VERSION 5.7 ;
  NOWIREEXTENSIONATPIN ON ;
  DIVIDERCHAR "/" ;
  BUSBITCHARS "[]" ;
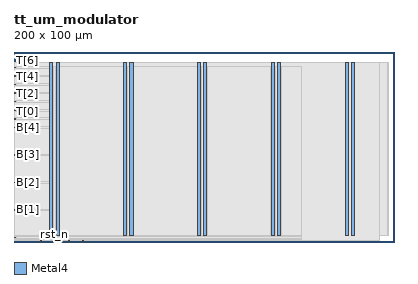
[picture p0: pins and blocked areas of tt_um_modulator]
MACRO tt_um_modulator
  CLASS BLOCK ;
  FOREIGN tt_um_modulator ;
  ORIGIN 0.000 0.000 ;
  SIZE 200.000 BY 100.000 ;
  PIN B[0]
    DIRECTION OUTPUT ;
    USE SIGNAL ;
    ANTENNADIFFAREA 1.055600 ;
    PORT
      LAYER Metal4 ;
        RECT 0.000 2.200 1.000 2.500 ;
    END
  END B[0]
  PIN B[1]
    DIRECTION OUTPUT ;
    USE SIGNAL ;
    ANTENNADIFFAREA 1.055600 ;
    PORT
      LAYER Metal4 ;
        RECT 0.000 16.700 1.000 17.000 ;
    END
  END B[1]
  PIN B[2]
    DIRECTION OUTPUT ;
    USE SIGNAL ;
    ANTENNADIFFAREA 1.055600 ;
    PORT
      LAYER Metal4 ;
        RECT 0.000 31.200 1.000 31.500 ;
    END
  END B[2]
  PIN B[3]
    DIRECTION OUTPUT ;
    USE SIGNAL ;
    ANTENNADIFFAREA 1.055600 ;
    PORT
      LAYER Metal4 ;
        RECT 0.000 45.700 1.000 46.000 ;
    END
  END B[3]
  PIN B[4]
    DIRECTION OUTPUT ;
    USE SIGNAL ;
    ANTENNADIFFAREA 1.055600 ;
    PORT
      LAYER Metal4 ;
        RECT 0.000 60.200 1.000 60.500 ;
    END
  END B[4]
  PIN T[0]
    DIRECTION OUTPUT ;
    USE SIGNAL ;
    ANTENNADIFFAREA 1.055600 ;
    PORT
      LAYER Metal4 ;
        RECT 0.000 64.700 1.000 65.000 ;
    END
  END T[0]
  PIN T[1]
    DIRECTION OUTPUT ;
    USE SIGNAL ;
    ANTENNADIFFAREA 1.055600 ;
    PORT
      LAYER Metal4 ;
        RECT 0.000 69.200 1.000 69.500 ;
    END
  END T[1]
  PIN T[2]
    DIRECTION OUTPUT ;
    USE SIGNAL ;
    ANTENNADIFFAREA 1.055600 ;
    PORT
      LAYER Metal4 ;
        RECT 0.000 73.700 1.000 74.000 ;
    END
  END T[2]
  PIN T[3]
    DIRECTION OUTPUT ;
    USE SIGNAL ;
    ANTENNADIFFAREA 1.055600 ;
    PORT
      LAYER Metal4 ;
        RECT 0.000 78.200 1.000 78.500 ;
    END
  END T[3]
  PIN T[4]
    DIRECTION OUTPUT ;
    USE SIGNAL ;
    ANTENNADIFFAREA 1.055600 ;
    PORT
      LAYER Metal4 ;
        RECT 0.000 82.700 1.000 83.000 ;
    END
  END T[4]
  PIN T[5]
    DIRECTION OUTPUT ;
    USE SIGNAL ;
    ANTENNADIFFAREA 1.055600 ;
    PORT
      LAYER Metal4 ;
        RECT 0.000 87.200 1.000 87.500 ;
    END
  END T[5]
  PIN T[6]
    DIRECTION OUTPUT ;
    USE SIGNAL ;
    ANTENNADIFFAREA 1.055600 ;
    PORT
      LAYER Metal4 ;
        RECT 0.000 91.700 1.000 92.000 ;
    END
  END T[6]
  PIN VGND
    DIRECTION INOUT ;
    USE GROUND ;
    PORT
      LAYER Metal4 ;
        RECT 22.180 3.620 23.780 94.380 ;
    END
    PORT
      LAYER Metal4 ;
        RECT 61.050 3.620 62.650 94.380 ;
    END
    PORT
      LAYER Metal4 ;
        RECT 99.920 3.620 101.520 94.380 ;
    END
    PORT
      LAYER Metal4 ;
        RECT 138.790 3.620 140.390 94.380 ;
    END
    PORT
      LAYER Metal4 ;
        RECT 177.660 3.620 179.260 94.380 ;
    END
  END VGND
  PIN VPWR
    DIRECTION INOUT ;
    USE POWER ;
    PORT
      LAYER Metal4 ;
        RECT 18.880 3.620 20.480 94.380 ;
    END
    PORT
      LAYER Metal4 ;
        RECT 57.750 3.620 59.350 94.380 ;
    END
    PORT
      LAYER Metal4 ;
        RECT 96.620 3.620 98.220 94.380 ;
    END
    PORT
      LAYER Metal4 ;
        RECT 135.490 3.620 137.090 94.380 ;
    END
    PORT
      LAYER Metal4 ;
        RECT 174.360 3.620 175.960 94.380 ;
    END
  END VPWR
  PIN clk
    DIRECTION INPUT ;
    USE SIGNAL ;
    ANTENNAGATEAREA 4.738000 ;
    PORT
      LAYER Metal4 ;
        RECT 14.000 0.000 14.300 1.000 ;
    END
  END clk
  PIN data_in
    DIRECTION INPUT ;
    USE SIGNAL ;
    ANTENNAGATEAREA 0.396000 ;
    PORT
      LAYER Metal4 ;
        RECT 28.700 0.000 29.000 1.000 ;
    END
  END data_in
  PIN enable
    DIRECTION INPUT ;
    USE SIGNAL ;
    ANTENNAGATEAREA 0.396000 ;
    PORT
      LAYER Metal4 ;
        RECT 36.050 0.000 36.350 1.000 ;
    END
  END enable
  PIN rst_n
    DIRECTION INPUT ;
    USE SIGNAL ;
    ANTENNAGATEAREA 0.396000 ;
    PORT
      LAYER Metal4 ;
        RECT 21.350 0.000 21.650 1.000 ;
    END
  END rst_n
  OBS
      LAYER Nwell ;
        RECT 2.930 3.490 196.990 94.510 ;
      LAYER Metal1 ;
        RECT 3.360 3.620 196.560 94.380 ;
      LAYER Metal2 ;
        RECT 5.180 1.770 192.500 94.270 ;
      LAYER Metal3 ;
        RECT 0.090 0.700 192.550 94.220 ;
      LAYER Metal4 ;
        RECT 0.140 92.300 18.580 92.310 ;
        RECT 1.300 91.400 18.580 92.300 ;
        RECT 0.140 87.800 18.580 91.400 ;
        RECT 1.300 86.900 18.580 87.800 ;
        RECT 0.140 83.300 18.580 86.900 ;
        RECT 1.300 82.400 18.580 83.300 ;
        RECT 0.140 78.800 18.580 82.400 ;
        RECT 1.300 77.900 18.580 78.800 ;
        RECT 0.140 74.300 18.580 77.900 ;
        RECT 1.300 73.400 18.580 74.300 ;
        RECT 0.140 69.800 18.580 73.400 ;
        RECT 1.300 68.900 18.580 69.800 ;
        RECT 0.140 65.300 18.580 68.900 ;
        RECT 1.300 64.400 18.580 65.300 ;
        RECT 0.140 60.800 18.580 64.400 ;
        RECT 1.300 59.900 18.580 60.800 ;
        RECT 0.140 46.300 18.580 59.900 ;
        RECT 1.300 45.400 18.580 46.300 ;
        RECT 0.140 31.800 18.580 45.400 ;
        RECT 1.300 30.900 18.580 31.800 ;
        RECT 0.140 17.300 18.580 30.900 ;
        RECT 1.300 16.400 18.580 17.300 ;
        RECT 0.140 3.320 18.580 16.400 ;
        RECT 20.780 3.320 21.880 92.310 ;
        RECT 24.080 3.320 57.450 92.310 ;
        RECT 59.650 3.320 60.750 92.310 ;
        RECT 62.950 3.320 96.320 92.310 ;
        RECT 98.520 3.320 99.620 92.310 ;
        RECT 101.820 3.320 135.190 92.310 ;
        RECT 137.390 3.320 138.490 92.310 ;
        RECT 140.690 3.320 151.060 92.310 ;
        RECT 0.140 2.800 151.060 3.320 ;
        RECT 1.300 1.900 151.060 2.800 ;
        RECT 0.140 1.300 151.060 1.900 ;
        RECT 0.140 0.650 13.700 1.300 ;
        RECT 14.600 0.650 21.050 1.300 ;
        RECT 21.950 0.650 28.400 1.300 ;
        RECT 29.300 0.650 35.750 1.300 ;
        RECT 36.650 0.650 151.060 1.300 ;
  END
END tt_um_modulator
END LIBRARY

